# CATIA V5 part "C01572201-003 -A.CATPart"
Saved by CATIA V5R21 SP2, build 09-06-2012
Part number: C01572201-003
Revision: ---
Description: PROPRIETARY NOTICE (do not delete / modify)  ***************************************************************************************************  LA SOCIETE EN COMMANDITE  AIRBUS CANADA  ("AIRBUS CANADA")  PAR  L'INTERMEDIAIRE  DE  SES  DIVISIONS  ET/OU  FILIALES  CORPORATIVES,  FOURNIT  LES PRESENTES  INFORMATIONS  AU  GOUVERNEMENT  A  TITRE CONFIDENTIEL. CES  INFORMATIONS ONT UNE TENEUR CONFIDENTIELLE,  AVEC DROITS DE PROPRIETE,  ET NOUS LES CONSIDERONS  EXCLUS  DE   L'APPLICATION  DE  LA LOI SUR L'ACCES A L'INFORMATION  (CANADA),  LES  LOIS  SUR  L'ACCES  A  L'INFORMATION  EUROPEENNES,  LE FREEDOM OF INFORMATION ACT (ETATS-UNIS) ET D'AUTRES LOIS SEMBLABLES. ELLES  PEUVENT  AUSSI  CONSTITUER DES SECRETS INDUSTRIELS DE NOTRE SOCIETE OU DE TIERCES PARTIES. LA DIVULGATION  PUBLIQUE  DE CES  INFORMATIONS NUIRAIT A AIRBUS CANADA OU A DES TIERCES PARTIES.  CES INFORMATIONS PEUVENT EGALEMENT CONTENIR  DES DONNEES QUI SONT CONTROLEE PAR DES LOIS DE CONTROLE DES EXPORTATIONS DU CANADA, L’EUROPE OU LES  ETATS-  UNIS. TOUTE EXPORTATION OU REEXPORTATION DE DONNEES CONTROLEES SANS AUTORISATION EST STRICTEMENT INTERDITE.  TOUTE INTENTION DE LES DIVULGUER EN TOUT OU EN PARTIE DEVRA ETRE SIGNIFIEE A L'AVANCE ET PAR ECRIT AU VICE-  PRESIDENT, SERVICES JURIDIQUES ET CONFORMITE ET SECRETAIRE CORPORATIF D'AIRBUS CANADA.    AIRBUS CANADA LIMITED PARTNERSHIP  ("AIRBUS CANADA"),  BY ITS AFFILIATES AND/OR SUBSIDIARIES, PROVIDES THIS  INFORMATION TO THE GOVERNMENT IN CONFIDENCE. THIS IS PROPRIETARY CONFIDENTIAL INFORMATION WHICH WE CONSIDER  EXCLUDED  FROM  THE  APPLICATION OF THE ACCESS TO INFORMATION ACT (CANADA),  THE FREEDOM OF INFORMATION ACT  (U.S.A.),  THE ACCESS TO INFORMATION LAWS IN EUROPE, AND OTHER SIMILAR LEGISLATION. AND MAY ALSO CONSTITUTE  TRADE SECRETS OF OUR  COMPANY OR THIRD PARTIES.  PUBLIC  RELEASE  OF  THIS INFORMATION  WOULD BE HARMFUL TO  AIRBUS CANADA OR THIRD PARTIES.  THIS  INFORMATION  MAY  ALSO  CONTAIN DATA THAT IS CONTROLLED BY CANADIAN,  EUROPEAN, OR U.S.A. EXPORT CONTROL LAWS. ANY UNAUTHORIZED EXPORT OR RE-EXPORT OF ANY EXPORT CONTROLLED DATA  IS STRICTLY PROHIBITED  ANY INTENTION TO DISCLOSE SUCH INFORMATION,  OR  PART THEREOF,  MUST BE NOTIFIED IN  ADVANCE AND IN WRITING TO THE VICE PRESIDENT, LEGAL AND COMPLIANCE AND CORPORATE SECRETARY OF AIRBUS CANADA.        LES RENSEIGNEMENTS,  LES DONNEES  ET  DESSINS  TECHNIQUES  DIVULGUES  DANS  LES PRESENTES SONT LA PROPRIETE  EXCLUSIVE DE LA SOCIETE EN COMMANDITE AIRBUS CANADA ("AIRBUS CANADA") OU COMPORTENT DES DROITS DE PROPRIETE  APPARTENANT  A  AUTRUI ET NE PEUVENT ETRE DIVULGUES  A  QUICONQUE  NI  UTILISES PAR QUI QUE CE SOIT SANS LE  CONSENTEMENT  ECRIT  D’AIRBUS  CANADA.  LE DETENTEUR DES  PRESENTES  S'ENGAGE, DANS TOUTES CIRCONSTANCES, A  GARDER CONFIDENTIELS LES DONNEES ET DESSINS TECHNIQUES QU'ELLES CONTIENNENT.   CE QUI PRECEDE NE S'APPLIQUE  PAS  AUX PERSONNES  QUI  ONT DES DROITS DE PROPRIETE SUR CES RENSEIGNEMENTS,  DONNEES TECHNIQUES ET DESSINS  DANS LA MESURE OU CES DROITS EXISTENT.    THE INFORMATION,  TECHNICAL DATA  AND  DESIGNS DISCLOSED HEREIN ARE THE EXCLUSIVE PROPERTY OF AIRBUS CANADA  LIMITED PARTNERSHIP  ("AIRBUS CANADA")  OR  CONTAIN PROPRIETARY RIGHTS OF OTHERS  AND ARE NOT TO BE USED OR  DISCLOSED  TO  OTHERS WITHOUT THE WRITTEN CONSENT OF AIRBUS CANADA.  THE RECIPIENT OF THIS DOCUMENT, BY ITS  RETENTION  AND  USE  AGREES TO  HOLD  IN  CONFIDENCE  THE  TECHNICAL DATA AND DESIGNS CONTAINED HEREIN. THE  FOREGOING SHALL NOT APPLY TO PERSONS HAVING PROPRIETARY RIGHTS TO SUCH INFORMATION,  TECHNICAL DATA OR SUCH  DESIGNS TO THE EXTENT THAT SUCH RIGHTS EXIST.    Copyright 2020 Airbus Canada Limited Partnership. All Rights Reserved.  ***********************************
Property "Title": "SHAFT, CAM, OWE"
Property "Dataset Type": "DETAIL"
Property "Supplier Name And CAGE Code": "AIRBUS CANADA LIMITED PARTNERSHIP L0J48"
Property "Major Supplier Code": "LP"
Property "3D Only": "Y"
Property "Material Form": "BAR - ROUND"
Property "Finish Code": "S010"
Property "PCCN": "2"
Property "TD Material Code": "-"
Property "Organization": "DESIGN"
Property "Dimensions": "DIMENSIONS ARE IN INCHES"
Property "Roughness": "ALL MACHINED SURFACES 125 Ra MAX"
Property "Eng. Tolerances": "LINEAR .XX= +/-.03; .XXX= +/-.010; ANGULAR= +/-0.5 DEG"
Property "Tool Design Tolerances": "LINEAR .X= +/-.06; .XX= +/-.015; .XXX= +/-.005; .XXXX= +/-.001; ANGULAR= +/-0.5 DEG"
Property "Design Authority Program": "BD-500"
Property "Color Coded": "N"
Property "Thickness": 0
Property "Inside Diameter": 0
Property "Outside Diameter": 0.75
Property "Length": 0
Property "Width": 0
Property "Wall": 0
Property "Alloy": "PH13-8MO"
Property "Final Condition": "H1000"
Property "MFG Process": "MACHINED"
Property "Material Specification Production": "AMS5629"
Property "Material Description Production": "CRES"
Property "Project": "BA"
Publications: "PartBody", "DATUM_A", "DATUM_B", "DATUM_C"
Material "ST-PH13-RO": density 7722.69 kg/m3, Young's modulus 1.95122e+11 Pa, Poisson ratio 0.28
Bounding box of the stored display mesh (mm): x -144.805 to 144.805, y -19.05 to 19.05, z -19.05 to 19.05
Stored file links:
  C:\Users\CQQZ006\Desktop\A220钢钛件\舱门\C01572201-003\C01572201-003 -A.CATPart

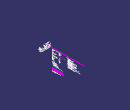
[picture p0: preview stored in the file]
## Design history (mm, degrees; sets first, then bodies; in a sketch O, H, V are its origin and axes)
AxisSystem1 "Absolute Axis System": origin (0, 0, 0), X (1, 0, 0), Y (0, 1, 0), Z (0, 0, 1)
Part_3D_Annotations1 "CATTPSSet"
Set1 "Pilot_Holes"
  Point1: (137.3124, 0, 0), in AxisSystem1
  Point2: (124.6124, 0, 0), in AxisSystem1
  Point3: (12.7, 0, 0), in AxisSystem1
  Point4: (-12.7, 0, 0), in AxisSystem1
  Point5: (-21.971, 0, 0), in AxisSystem1
  Point6: (-124.6124, 0, 0), in AxisSystem1
  Point7: (-137.3124, 0, 0), in AxisSystem1
  Line1: type PtDir, RefPoint Point1, Direction Plane2, Start -19.05, End 19.05
  Line2: type PtDir, RefPoint Point2, Direction Plane1, Start -19.05, End 19.05
  Line3: type PtDir, RefPoint Point3, Direction (0, 0, 1), Start -19.05, End 19.05
  Line4: type PtDir, RefPoint Point4, Direction edge [ZX plane of AxisSystem1 | YZ plane of AxisSystem1], Start -19.05, End 19.05
  Line5: type PtDir, RefPoint Point5, Direction (0, 1, 0), Start -19.05, End 19.05
  Line6: type PtDir, RefPoint Point6, Direction Plane1, Start -19.05, End 19.05
  Line7: type PtDir, RefPoint Point7, Direction Plane2, Start -19.05, End 19.05
Set2 "Master_Geometry"
  Extract1 "DATUM_A": ExtractElem face of Shaft1 from Sketch1.L11
  Extract2 "DATUM_B": ExtractElem face of Shaft1 from Sketch1.L7
  Extract3 "DATUM_C": ExtractElem face of Shaft1 from Sketch1.L3
Set4 "Construction_Geometry"
  Set5 "Sketches_Not_Used_By_PartBody"
    Plane1: type Angle, RefPlane zx-plane, Direction X axis, Angle 54.5
    Plane2: type Angle, RefPlane Plane1, Direction X axis, Angle 90
Body1 (main body)
  Sketch1 on zx-plane, origin (0, 0, 0), H (-1, 0, 0), V (0, 0, 1)
    axis line L1 (-157.371, 0) -> (166.3068, 0)
    point P1 (-157.371, 0)
    line L2 (-144.8054, 4.7625) -> (-49.53, 4.7625)
    line L3 (144.8054, 4.7625) -> (144.8054, 7.1031)
    line L4 (144.8054, 7.1031) -> (114.1032, 7.1031)
    line L5 (111.9124, 7.493) -> (64.4987, 7.493)
    point P3 (62.23, 7.493)
    construction line L6 (62.23, 7.493) -> (62.23, 7.9121)
    point P4 (62.23, 7.9121)
    line L7 (62.23, 7.9121) -> (8.6187, 7.9121)
    line L8 (-8.6187, 7.9121) -> (-62.23, 7.9121)
    point P5 (-62.23, 7.9121)
    construction line L9 (-62.23, 7.9121) -> (-62.23, 7.493)
    point P6 (-62.23, 7.493)
    line L10 (-64.4987, 7.493) -> (-111.9124, 7.493)
    line L11 (-114.1032, 7.1031) -> (-144.8054, 7.1031)
    line L12 (-144.8054, 7.1031) -> (-144.8054, 4.7625)
    construction line L13 (0, 32.2264) -> (0, -20.5665)
    point P7 (0, 32.2264)
    point P10 (-111.9124, 7.493)
    arc A1 centre (-64.4987, 13.843) radius 6.35 from (-64.4987, 7.493) to (-62.23, 7.9121) ccw
    arc A2 centre (64.4987, 13.843) radius 6.35 from (62.23, 7.9121) to (64.4987, 7.493) ccw
    point P16 (111.9124, 7.493)
    line L14 (-6.35, 7.493) -> (6.35, 7.493)
    arc A3 centre (-6.35, 13.843) radius 6.35 from (-8.6187, 7.9121) to (-6.35, 7.493) ccw
    point P19 (-6.35, 13.843)
    arc A4 centre (6.35, 13.843) radius 6.35 from (6.35, 7.493) to (8.6187, 7.9121) ccw
    point P20 (6.35, 13.843)
    arc A5 centre (-114.1032, 13.4531) radius 6.35 from (-114.1032, 7.1031) to (-111.9124, 7.493) ccw
    arc A6 centre (114.1032, 13.4531) radius 6.35 from (111.9124, 7.493) to (114.1032, 7.1031) ccw
    line L15 (49.53, 4.7625) -> (48.864, 3.9688)
    point P27 (49.53, 4.7625)
    line L16 (-49.53, 4.7625) -> (-48.864, 3.9688)
    line L17 (49.53, 4.7625) -> (144.8054, 4.7625)
    line L18 (-48.864, 3.9688) -> (48.864, 3.9688)
    distance L12 L3 = 289.6108
    distance L1 L11 = 7.1031
    distance L10 L1 = 7.493
    radius A1 = 6.35
    radius A2 = 6.35
    radius A4 = 6.35
    distance P19 P20 = 12.7
    distance L8 L1 = 7.9121
    distance L9 L13 = 62.23
    distance L12 P10 = 32.893
    radius A5 = 6.35
    distance L3 P16 = 32.893 {= Sketch1.distance(L12 P10)}
    distance L4 L1 = 7.1031 {= Sketch1.distance(L1 L11)}
    radius A6 = 6.35 {= Sketch1.radius(A1)}
    angle L15 L1 = 50
    "Radius" L18 L1 = 3.9688
    "Radius" L2 L1 = 4.7625
    distance L13 P27 = 49.53
    coincidence: P1 H, P6 L5, P7 V, A1 P5, P5 L8, P6 L10, A2 P4, P3 L5, P4 L7, L7 L8, L14 L10, P27 L2, L2 L17
    horizontal: L1 H, L2 H, L4 H, L5 H, L7 H, L8 H, L10 H, L11 H, L14 H, L17 H, L18 H
    vertical: L3 V, L6 V, L9 V, L12 V, L13 V
    symmetry: L12 L3 L13, L9 L6 L13, P19 P20 L13, L15 L16 L13
    tangency: A1 L10, A2 L5, A4 L14, A3 L14, A5 L11, A6 L4
  Shaft1: profile Sketch1, axis Sketch1.L1, angle 360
